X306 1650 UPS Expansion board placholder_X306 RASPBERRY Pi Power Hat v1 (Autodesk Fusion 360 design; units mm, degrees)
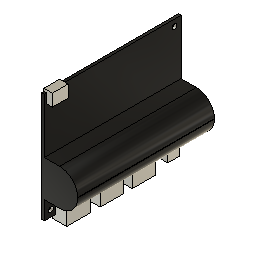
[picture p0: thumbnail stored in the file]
base_feature "Base Feature"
